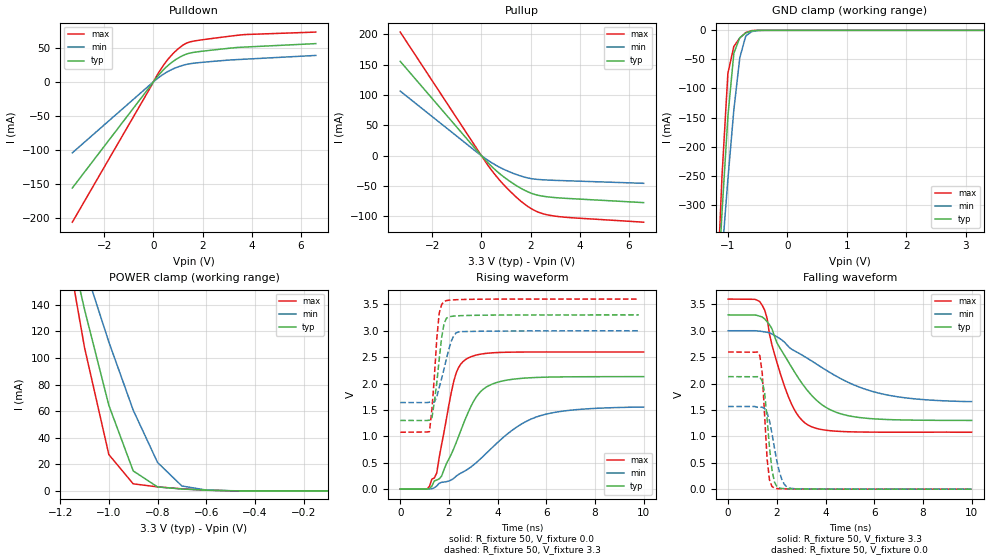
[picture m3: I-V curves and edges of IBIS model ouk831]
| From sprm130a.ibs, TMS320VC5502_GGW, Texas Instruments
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[Model]   ouk831
Model_type   3-state
Enable   Active-Low
Polarity   Non-Inverting
| signals   A, GZ, Y
Vmeas = 1.5
|   typ   min   max
C_comp   1.9825p   1.8925p   2.1938p
|   typ   min   max
[Temperature Range]   25   -40   125
|   typ   min   max
[Voltage Range]   3.30V   3.00V   3.60V
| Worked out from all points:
|   slope of the pulldown table from 0 to 0.495 V, typ, clamps not added: 24 ohm
|   slope of the pullup table from 0 to 0.495 V, typ, clamps not added: 23.8 ohm
|   GND clamp passes 1 mA (typ) near -0.60 V on its own axis
|   POWER clamp passes 1 mA (typ) near -0.65 V on its own axis
|   rising waveform, R_fixture 50, V_fixture 0.0: 20-80 % time 1.22ns typ, 2.5ns min, 648ps max; typ from 0 V to 2.13 V
|   falling waveform, R_fixture 50, V_fixture 3.3: 20-80 % time 1.69ns typ, 3.01ns min, 990ps max; typ from 3.3 V to 1.3 V
|   rising waveform, R_fixture 50, V_fixture 3.3: 20-80 % time 297ps typ, 453ps min, 239ps max; typ from 1.3 V to 3.3 V
|   falling waveform, R_fixture 50, V_fixture 0.0: 20-80 % time 263ps typ, 400ps min, 199ps max; typ from 2.13 V to 0 V
[Pulldown]
|   Voltage   I(typ)   I(min)   I(max)
-3.3V     -155.6mA   -104.1mA   -205.6mA
200mV     9.243mA    5.866mA    12.7mA
600mV     24.13mA    15.28mA    33.3mA
800mV     29.87mA    18.87mA    41.37mA
1.1V      36.63mA    23.02mA    51.08mA
1.3V      39.97mA    25.04mA    55.82mA
1.6V      42.83mA    27mA       59.29mA
3.5V      50.44mA    32.65mA    68.4mA
6.6V      55.87mA    38.54mA    72.75mA
[GND_clamp]
|   Voltage   I(typ)   I(min)   I(max)
-3.3V     -4.907A    -3.696A    -6.377A
-1.2V     -502.7mA   -527mA     -494.6mA
-1.1V     -315.4mA   -388.3mA   -252.9mA
-1V       -148.3mA   -256.2mA   -74.02mA
-900mV    -39.47mA   -137mA     -27.69mA
-800mV    -12.62mA   -47.18mA   -13.24mA
-700mV    -4.559mA   -9.795mA   -3.853mA
-600mV    -881.5uA   -2.2mA     -437.5uA
-400mV    -4.511uA   -47.56uA   -461.1nA
3.3V      222pA      1.904uA    88.82pA
[Pullup]
|   Voltage   I(typ)   I(min)   I(max)
-3.3V     155.5mA    106.5mA    203.9mA
-200mV    9.306mA    6.233mA    12.42mA
300mV     -13.07mA   -8.546mA   -17.75mA
600mV     -24.68mA   -16mA      -33.65mA
900mV     -34.78mA   -22.33mA   -47.64mA
1.4V      -48.81mA   -30.78mA   -67.77mA
1.7V      -55.9mA    -34.78mA   -78.19mA
2V        -61.53mA   -37.68mA   -86.71mA
2.3V      -65.31mA   -39.22mA   -93.01mA
2.9V      -68.83mA   -40.61mA   -99.22mA
3.7V      -71.03mA   -41.73mA   -102.5mA
6.6V      -77.46mA   -45.65mA   -109.8mA
[POWER_clamp]
|   Voltage   I(typ)   I(min)   I(max)
-3.3V     2.105A     1.588A     2.734A
-1.2V     217.1mA    228.2mA    212.4mA
-1.1V     136.6mA    168.7mA    107.9mA
-1V       64.4mA     112mA      27.37mA
-900mV    15.08mA    60.81mA    5.337mA
-800mV    3.01mA     21.44mA    3.051mA
-700mV    1.426mA    3.716mA    1.578mA
-600mV    596.1uA    671uA      553.1uA
-100mV    532.9pA    9.903nA    222pA
[Ramp]
|   I(typ)   I(min)   I(max)
dV/dt_r   1.278/1.221n   0.933/2.501n   1.559/0.646n
dV/dt_f   1.199/1.686n   0.806/3.015n   1.513/0.989n
[Rising Waveform]
R_fixture = 50
V_fixture = 0.0
|  pu_on
|  TIME   V(typ)   V(min)   V(max)
0s        3nV        14nV       2nV
1.1ns     -106.9uV   -189uV     2.744mV
1.4ns     154.8mV    26.97mV    211.4mV
1.5ns     173.4mV    58.87mV    306.4mV
1.7ns     249.3mV    129.8mV    846.7mV
2.2ns     769.4mV    204.7mV    2.046V
2.8ns     1.464V     386.2mV    2.486V
3.7ns     1.974V     752.5mV    2.579V
5.6ns     2.115V     1.368V     2.597V
10ns      2.131V     1.554V     2.598V
[Falling Waveform]
R_fixture = 50
V_fixture = 3.3
V_fixture_min = 3.0
V_fixture_max = 3.6
|  pd_on
|  TIME   V(typ)   V(min)   V(max)
0s        3.3V       3V         3.6V
1.4ns     3.26V      2.985V     3.48V
1.9ns     2.901V     2.914V     2.565V
2.4ns     2.469V     2.74V      1.84V
2.8ns     2.165V     2.6V       1.442V
3.3ns     1.844V     2.466V     1.211V
4.1ns     1.527V     2.232V     1.112V
5.1ns     1.377V     1.988V     1.085V
7ns       1.312V     1.747V     1.078V
10ns      1.302V     1.659V     1.078V
[Rising Waveform]
R_fixture = 50
V_fixture = 3.3
V_fixture_min = 3.0
V_fixture_max = 3.6
|  pd_off
|  TIME   V(typ)   V(min)   V(max)
0s        1.301V     1.64V      1.078V
1.2ns     1.306V     1.646V     1.089V
1.3ns     1.343V     1.65V      1.502V
1.5ns     2.012V     1.743V     2.841V
1.6ns     2.453V     1.922V     3.331V
1.7ns     2.869V     2.094V     3.496V
1.8ns     3.138V     2.279V     3.554V
2.1ns     3.272V     2.806V     3.583V
2.4ns     3.284V     2.978V     3.589V
9.8ns     3.3V       3V         3.6V
[Falling Waveform]
R_fixture = 50
V_fixture = 0.0
|  pu_off
|  TIME   V(typ)   V(min)   V(max)
0s        2.131V     1.565V     2.598V
1.3ns     2.125V     1.554V     2.528V
1.4ns     2.046V     1.551V     2.198V
1.5ns     1.815V     1.526V     1.379V
1.6ns     1.333V     1.447V     573.5mV
1.7ns     780mV      1.291V     169.2mV
1.9ns     136.3mV    784.4mV    20.03mV
2.2ns     14.26mV    192.5mV    6.948mV
2.5ns     6.754mV    21.9mV     4.056mV
10ns      1.954uV    67.49uV    634nV
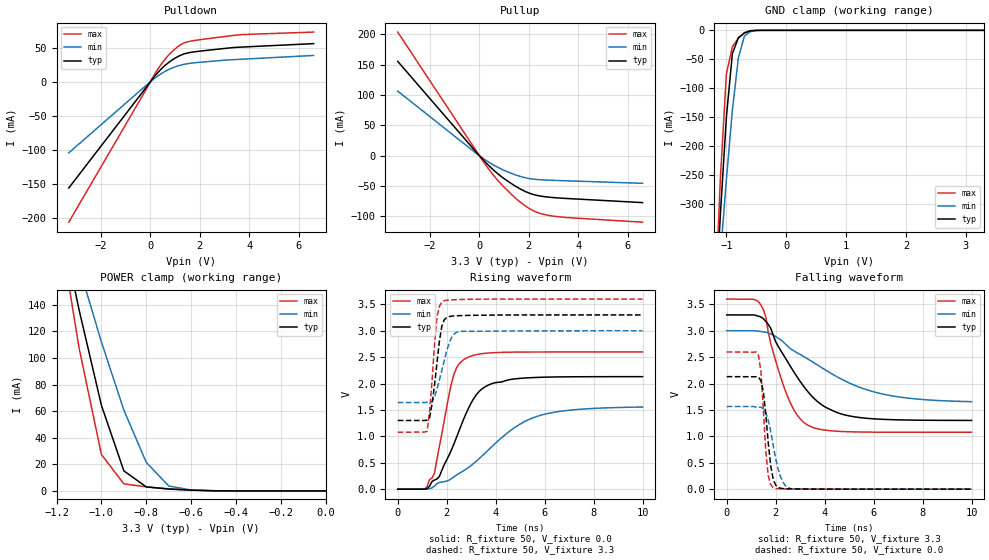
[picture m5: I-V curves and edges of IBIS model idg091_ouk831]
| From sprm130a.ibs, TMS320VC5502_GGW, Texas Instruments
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[Model]   idg091_ouk831
Model_type   I/O
Vinh = 2.00
Vinl = 0.80
Enable   Active-Low
Polarity   Non-Inverting
| signals   A, GZ, Y
Vmeas = 1.5
|   typ   min   max
C_comp   2.425p   2.416p   2.427p
|   typ   min   max
[Temperature Range]   25   -40   125
|   typ   min   max
[Voltage Range]   3.30V   3.00V   3.60V
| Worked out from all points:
|   slope of the pulldown table from 0 to 0.495 V, typ, clamps not added: 24 ohm
|   slope of the pullup table from 0 to 0.495 V, typ, clamps not added: 23.8 ohm
|   GND clamp passes 1 mA (typ) near -0.60 V on its own axis
|   POWER clamp passes 1 mA (typ) near -0.65 V on its own axis
|   rising waveform, R_fixture 50, V_fixture 0.0: 20-80 % time 1.23ns typ, 2.49ns min, 654ps max; typ from 0 V to 2.13 V
|   falling waveform, R_fixture 50, V_fixture 3.3: 20-80 % time 1.69ns typ, 3.02ns min, 1ns max; typ from 3.3 V to 1.3 V
|   rising waveform, R_fixture 50, V_fixture 3.3: 20-80 % time 309ps typ, 462ps min, 249ps max; typ from 1.3 V to 3.3 V
|   falling waveform, R_fixture 50, V_fixture 0.0: 20-80 % time 276ps typ, 422ps min, 219ps max; typ from 2.13 V to 0 V
[Pulldown]
|   Voltage   I(typ)   I(min)   I(max)
-3.3V     -155.6mA   -104.1mA   -205.6mA
200mV     9.243mA    5.866mA    12.7mA
600mV     24.13mA    15.28mA    33.3mA
800mV     29.87mA    18.87mA    41.37mA
1.1V      36.63mA    23.02mA    51.08mA
1.3V      39.97mA    25.04mA    55.82mA
1.6V      42.83mA    27mA       59.29mA
3.5V      50.44mA    32.65mA    68.4mA
6.6V      55.87mA    38.54mA    72.75mA
[GND_clamp]
|   Voltage   I(typ)   I(min)   I(max)
-3.3V     -4.92A     -3.705A    -6.392A
-1.2V     -504.4mA   -528.6mA   -496.3mA
-1.1V     -316.6mA   -389.6mA   -254.1mA
-1V       -149.2mA   -257.2mA   -74.8mA
-900mV    -39.96mA   -137.7mA   -28.16mA
-800mV    -12.87mA   -47.62mA   -13.47mA
-700mV    -4.652mA   -10.02mA   -3.929mA
-600mV    -901uA     -2.282mA   -447.5uA
-400mV    -4.618uA   -49.29uA   -472.1nA
3.3V      177.6pA    1.904uA    222pA
[Pullup]
|   Voltage   I(typ)   I(min)   I(max)
-3.3V     155.5mA    106.5mA    203.9mA
-200mV    9.306mA    6.233mA    12.42mA
300mV     -13.07mA   -8.546mA   -17.75mA
600mV     -24.68mA   -16mA      -33.65mA
900mV     -34.78mA   -22.33mA   -47.64mA
1.4V      -48.81mA   -30.78mA   -67.77mA
1.7V      -55.9mA    -34.78mA   -78.19mA
2V        -61.53mA   -37.68mA   -86.71mA
2.3V      -65.31mA   -39.22mA   -93.01mA
2.9V      -68.83mA   -40.61mA   -99.22mA
3.7V      -71.03mA   -41.73mA   -102.5mA
6.6V      -77.46mA   -45.65mA   -109.8mA
[POWER_clamp]
|   Voltage   I(typ)   I(min)   I(max)
-3.3V     2.105A     1.588A     2.734A
-1.2V     217.1mA    228.2mA    212.4mA
-1.1V     136.6mA    168.7mA    107.9mA
-1V       64.4mA     112mA      27.37mA
-900mV    15.08mA    60.81mA    5.337mA
-800mV    3.01mA     21.44mA    3.051mA
-700mV    1.426mA    3.716mA    1.578mA
-600mV    596.1uA    671uA      553.1uA
0V        1pA        1pA        1pA
[Ramp]
|   I(typ)   I(min)   I(max)
dV/dt_r   1.278/1.223n   0.933/2.494n   1.559/0.650n
dV/dt_f   1.199/1.695n   0.806/3.019n   1.513/0.998n
[Rising Waveform]
R_fixture = 50
V_fixture = 0.0
|  pu_on
|  TIME   V(typ)   V(min)   V(max)
0s        3nV        15nV       3nV
1.1ns     -42.55uV   -125uV     2.351mV
1.5ns     172.1mV    56.5mV     296.1mV
2.2ns     750.8mV    200.4mV    2.015V
2.4ns     979.3mV    267.4mV    2.296V
2.8ns     1.442V     381mV      2.482V
3.2ns     1.781V     524.5mV    2.547V
3.7ns     1.97V      741.5mV    2.578V
5.6ns     2.115V     1.365V     2.597V
10ns      2.131V     1.554V     2.598V
[Falling Waveform]
R_fixture = 50
V_fixture = 3.3
V_fixture_min = 3.0
V_fixture_max = 3.6
|  pd_on
|  TIME   V(typ)   V(min)   V(max)
0s        3.3V       3V         3.6V
1.4ns     3.261V     2.986V     3.486V
1.8ns     3.046V     2.94V      2.762V
2.4ns     2.481V     2.747V     1.861V
2.8ns     2.179V     2.603V     1.46V
3.3ns     1.855V     2.47V      1.215V
4ns       1.562V     2.266V     1.119V
5.1ns     1.379V     1.992V     1.086V
7ns       1.313V     1.749V     1.078V
10ns      1.302V     1.657V     1.078V
[Rising Waveform]
R_fixture = 50
V_fixture = 3.3
V_fixture_min = 3.0
V_fixture_max = 3.6
|  pd_off
|  TIME   V(typ)   V(min)   V(max)
0s        1.301V     1.64V      1.078V
1.2ns     1.307V     1.645V     1.093V
1.3ns     1.352V     1.649V     1.457V
1.4ns     1.607V     1.655V     2.035V
1.6ns     2.378V     1.894V     3.25V
1.8ns     3.083V     2.244V     3.542V
1.9ns     3.207V     2.434V     3.57V
2.2ns     3.276V     2.871V     3.585V
2.5ns     3.286V     2.982V     3.591V
10ns      3.3V       3V         3.6V
[Falling Waveform]
R_fixture = 50
V_fixture = 0.0
|  pu_off
|  TIME   V(typ)   V(min)   V(max)
0s        2.131V     1.565V     2.598V
1.3ns     2.123V     1.554V     2.53V
1.4ns     2.05V      1.55V      2.221V
1.5ns     1.84V      1.524V     1.488V
1.6ns     1.398V     1.451V     692.2mV
1.7ns     864.6mV    1.306V     247mV
1.9ns     189.8mV    831.4mV    26.7mV
2.2ns     17.49mV    235mV      6.826mV
2.6ns     5.644mV    11.73mV    3.52mV
10ns      2.536uV    60.88uV    9.272uV
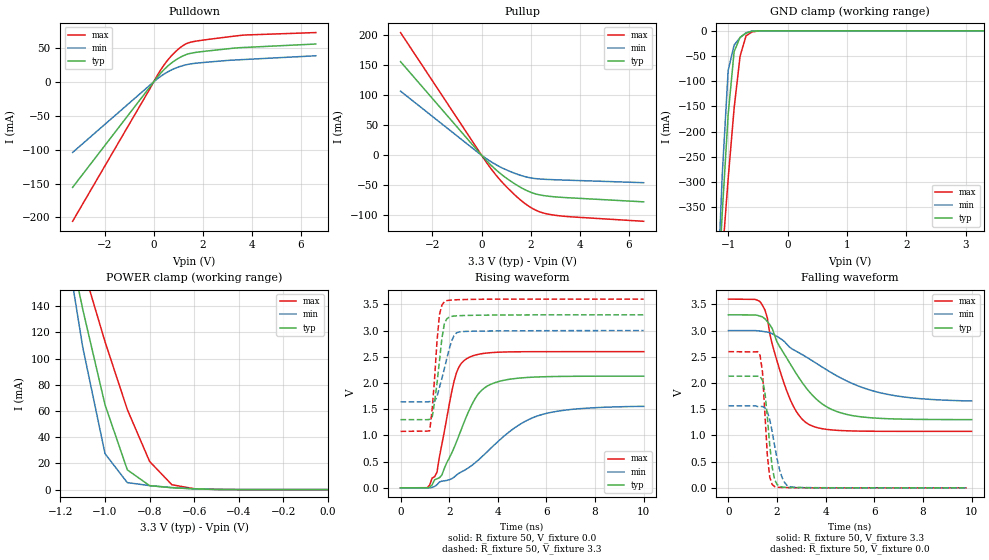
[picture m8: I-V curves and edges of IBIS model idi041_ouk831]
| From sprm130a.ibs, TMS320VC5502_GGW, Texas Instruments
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[Model]   idi041_ouk831
Model_type   I/O
Vinh = 2.00
Vinl = 0.80
Enable   Active-Low
Polarity   Non-Inverting
| signals   A, GZ, Y
Vmeas = 1.5
|   typ   min   max
C_comp   1.7165p   1.6246p   1.9241p
|   typ   min   max
[Temperature Range]   25   -40   125
|   typ   min   max
[Voltage Range]   3.30V   3.00V   3.60V
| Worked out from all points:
|   slope of the pulldown table from 0 to 0.495 V, typ, clamps not added: 24 ohm
|   slope of the pullup table from 0 to 0.495 V, typ, clamps not added: 23.8 ohm
|   GND clamp passes 1 mA (typ) near -0.60 V on its own axis
|   POWER clamp passes 1 mA (typ) near -0.65 V on its own axis
|   rising waveform, R_fixture 50, V_fixture 0.0: 20-80 % time 1.22ns typ, 2.5ns min, 653ps max; typ from 0 V to 2.13 V
|   falling waveform, R_fixture 50, V_fixture 3.3: 20-80 % time 1.69ns typ, 3.01ns min, 996ps max; typ from 3.3 V to 1.3 V
|   rising waveform, R_fixture 50, V_fixture 3.3: 20-80 % time 302ps typ, 454ps min, 244ps max; typ from 1.3 V to 3.3 V
|   falling waveform, R_fixture 50, V_fixture 0.0: 20-80 % time 267ps typ, 406ps min, 207ps max; typ from 2.13 V to 0 V
[Pulldown]
|   Voltage   I(typ)   I(min)   I(max)
-3.3V     -155.6mA   -104.1mA   -205.7mA
200mV     9.245mA    5.867mA    12.7mA
600mV     24.13mA    15.28mA    33.3mA
800mV     29.87mA    18.87mA    41.37mA
1.1V      36.63mA    23.02mA    51.08mA
1.3V      39.97mA    25.04mA    55.82mA
1.6V      42.83mA    27mA       59.29mA
3.5V      50.44mA    32.65mA    68.4mA
6.6V      55.85mA    38.51mA    72.74mA
[GND_clamp]
|   Voltage   I(typ)   I(min)   I(max)
-3.3V     -5.787A    -7.522A    -4.358A
-1.2V     -582.8mA   -571.6mA   -612.7mA
-1.1V     -361.8mA   -286.6mA   -448.9mA
-1V       -165.7mA   -78.53mA   -293.3mA
-900mV    -41.31mA   -28.3mA    -153.6mA
-800mV    -12.91mA   -13.52mA   -50.55mA
-700mV    -4.659mA   -3.937mA   -10.09mA
-600mV    -901.5uA   -447.7uA   -2.271mA
-400mV    -4.618uA   -472nA     -49.07uA
3.3V      133.2pA    0A         1.904uA
[Pullup]
|   Voltage   I(typ)   I(min)   I(max)
-3.3V     155.5mA    106.5mA    203.8mA
-200mV    9.305mA    6.232mA    12.42mA
300mV     -13.07mA   -8.545mA   -17.75mA
600mV     -24.68mA   -16mA      -33.64mA
900mV     -34.78mA   -22.33mA   -47.63mA
1.4V      -48.81mA   -30.78mA   -67.76mA
1.7V      -55.89mA   -34.78mA   -78.18mA
2V        -61.53mA   -37.68mA   -86.7mA
2.3V      -65.31mA   -39.22mA   -93.01mA
2.9V      -68.84mA   -40.61mA   -99.22mA
3.7V      -71.03mA   -41.73mA   -102.5mA
6.6V      -77.47mA   -45.64mA   -109.8mA
[POWER_clamp]
|   Voltage   I(typ)   I(min)   I(max)
-3.3V     2.13A      2.766A     1.607A
-1.2V     219.2mA    214.4mA    230.5mA
-1.1V     137.7mA    108.7mA    170.3mA
-1V       64.77mA    27.43mA    112.9mA
-900mV    15.1mA     5.337mA    61.17mA
-800mV    3.01mA     3.051mA    21.5mA
-700mV    1.426mA    1.578mA    3.717mA
-600mV    596.1uA    553.1uA    671uA
0V        399.7pA    88.82pA    9.948nA
[Ramp]
|   I(typ)   I(min)   I(max)
dV/dt_r   1.278/1.225n   0.933/2.496n   1.559/0.650n
dV/dt_f   1.199/1.692n   0.806/3.021n   1.513/0.996n
[Rising Waveform]
R_fixture = 50
V_fixture = 0.0
|  pu_on
|  TIME   V(typ)   V(min)   V(max)
0s        3nV        16nV       2nV
1.1ns     -136.2uV   -227.7uV   2.664mV
1.5ns     172.5mV    58.47mV    298.6mV
1.7ns     244.2mV    128.6mV    829.6mV
2.2ns     762.6mV    202.4mV    2.033V
2.4ns     994mV      278.2mV    2.305V
2.8ns     1.457V     384mV      2.484V
3.6ns     1.95V      704.6mV    2.574V
5.6ns     2.115V     1.366V     2.597V
10ns      2.131V     1.554V     2.598V
[Falling Waveform]
R_fixture = 50
V_fixture = 3.3
V_fixture_min = 3.0
V_fixture_max = 3.6
|  pd_on
|  TIME   V(typ)   V(min)   V(max)
0s        3.3V       3V         3.6V
1.4ns     3.261V     2.986V     3.482V
1.8ns     3.04V      2.939V     2.741V
2.4ns     2.474V     2.742V     1.847V
2.8ns     2.171V     2.602V     1.452V
3.3ns     1.848V     2.468V     1.212V
4.1ns     1.53V      2.234V     1.112V
5.1ns     1.378V     1.989V     1.085V
7.1ns     1.312V     1.741V     1.078V
10ns      1.302V     1.659V     1.078V
[Rising Waveform]
R_fixture = 50
V_fixture = 3.3
V_fixture_min = 3.0
V_fixture_max = 3.6
|  pd_off
|  TIME   V(typ)   V(min)   V(max)
0s        1.301V     1.641V     1.078V
1.2ns     1.306V     1.646V     1.089V
1.3ns     1.342V     1.649V     1.488V
1.5ns     1.991V     1.741V     2.795V
1.6ns     2.42V      1.914V     3.303V
1.7ns     2.844V     2.083V     3.482V
1.8ns     3.124V     2.267V     3.55V
2.1ns     3.27V      2.799V     3.583V
2.4ns     3.284V     2.974V     3.589V
10ns      3.3V       3V         3.6V
[Falling Waveform]
R_fixture = 50
V_fixture = 0.0
|  pu_off
|  TIME   V(typ)   V(min)   V(max)
0s        2.131V     1.565V     2.598V
1.3ns     2.125V     1.554V     2.531V
1.4ns     2.049V     1.551V     2.211V
1.5ns     1.825V     1.527V     1.412V
1.6ns     1.355V     1.45V      617.1mV
1.7ns     806.4mV    1.298V     200.8mV
1.9ns     159.2mV    803.3mV    23.63mV
2.2ns     16.04mV    204.3mV    7.236mV
2.5ns     7.055mV    25.79mV    4.002mV
9.8ns     3.44uV     67.92uV    1.382uV
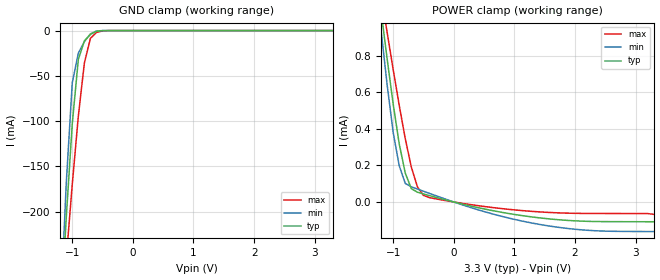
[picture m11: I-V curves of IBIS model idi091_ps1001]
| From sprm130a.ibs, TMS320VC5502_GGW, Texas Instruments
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[Model]   idi091_ps1001
| Input with pullup
Model_type   Input
Polarity   Non-Inverting
| signals   A, Y
Vinl = 0.8V
Vinh = 2.0V
|   typ   min   max
C_comp   1.4592p   1.4336p   1.5063p
|   typ   min   max
[Temperature Range]   25   -40   125
|   typ   min   max
[Voltage Range]   3.30V   3.00V   3.60V
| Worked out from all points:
|   GND clamp passes 1 mA (typ) near -0.61 V on its own axis
|   POWER clamp passes 1 mA (typ) near -1.18 V on its own axis
[GND_clamp]
|   Voltage   I(typ)   I(min)   I(max)
-3.3V     -3.046A    -3.955A    -2.3A
-1.2V     -324.1mA   -319.7mA   -338.8mA
-1.1V     -207.5mA   -169.7mA   -252.5mA
-1V       -102.7mA   -57.61mA   -169.8mA
-900mV    -31.8mA    -24.95mA   -94.42mA
-800mV    -11.42mA   -12.07mA   -35.62mA
-700mV    -4.192mA   -3.56mA    -8.508mA
-600mV    -819.1uA   -409.8uA   -2.049mA
-500mV    -75.22uA   -19.35uA   -368.2uA
-400mV    -4.217uA   -434.7nA   -45.05uA
3.3V      222pA      133.2pA    35.04nA
[POWER_clamp]
|   Voltage   I(typ)   I(min)   I(max)
-3.3V     6.905mA    7.841mA    5.744mA
-1.2V     1.047mA    943.6uA    1.139mA
-1.1V     786.2uA    644.3uA    930.8uA
-1V       537.8uA    382uA      726.9uA
-900mV    318.6uA    198.8uA    530.3uA
-800mV    158.1uA    101.7uA    346.8uA
-700mV    72.97uA    83uA       190.9uA
-600mV    53.62uA    70.93uA    83.38uA
-500mV    44.09uA    58.94uA    36.26uA
500mV     -38.02uA   -52.48uA   -24.54uA
1.4V      -86.44uA   -122uA     -53.97uA
3.3V      -108.3uA   -162.1uA   -67.64uA
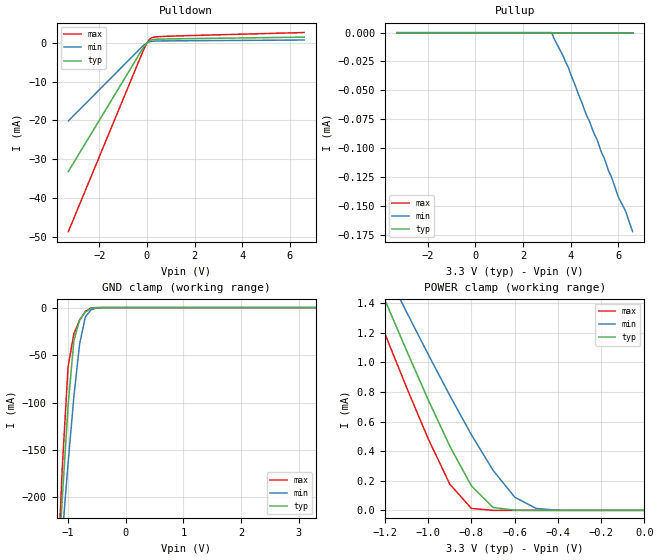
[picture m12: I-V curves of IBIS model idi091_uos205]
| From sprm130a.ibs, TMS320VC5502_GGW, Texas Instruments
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[Model]   idi091_uos205
| Open drain output with input buffer
Model_type   I/O_open_drain
Vinh = 2.00
Vinl = 0.80
Enable   Active-Low
Polarity   Non-Inverting
| signals   A, GZ, Y
Vmeas = 1.5
|   typ   min   max
C_comp   3.010p   2.992p   3.013p
|   typ   min   max
[Temperature Range]   25   -40   125
|   typ   min   max
[Voltage Range]   3.30V   3.00V   3.60V
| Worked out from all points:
|   slope of the pulldown table from 0 to 0.495 V, typ, clamps not added: 511 ohm
|   GND clamp passes 1 mA (typ) near -0.60 V on its own axis
|   POWER clamp passes 1 mA (typ) near -1.08 V on its own axis
[Pulldown]
|   Voltage   I(typ)   I(min)   I(max)
-3.3V     -33.16mA   -20.11mA   -48.66mA
-200mV    -1.676mA   -953uA     -2.637mA
0V        0A         0A         -1uA
100mV     530uA      281uA      888uA
300mV     907uA      480uA      1.509mA
700mV     1.004mA    523uA      1.686mA
6.6V      1.5mA      758uA      2.684mA
[GND_clamp]
|   Voltage   I(typ)   I(min)   I(max)
-3.3V     -2.797A    -2.112A    -3.63A
-1.2V     -307.5mA   -319mA     -305.9mA
-1.1V     -200.8mA   -240.1mA   -168.3mA
-1V       -103.9mA   -164.3mA   -62.58mA
-900mV    -35.2mA    -94.59mA   -27.75mA
-800mV    -12.79mA   -38.44mA   -13.42mA
-700mV    -4.685mA   -9.784mA   -3.964mA
-600mV    -917.7uA   -2.332mA   -456.8uA
-500mV    -84.37uA   -416.9uA   -21.55uA
-400mV    -4.73uA    -50.82uA   -483.2nA
3.3V      266.4pA    59.73nA    177.6pA
[Pullup]
|   Voltage   I(typ)   I(min)   I(max)
-3.3V     0A         0A         0A
3.2V      0A         0A         0A
3.9V      0A         -30uA      0A
4.6V      0A         -68uA      0A
4.8V      0A         -77uA      0A
5.1V      0A         -92uA      0A
5.3V      0A         -104uA     0A
5.4V      0A         -108uA     0A
5.7V      0A         -124uA     0A
6V        0A         -142uA     0A
6.3V      0A         -154uA     0A
6.6V      0A         -172uA     0A
[POWER_clamp]
|   Voltage   I(typ)   I(min)   I(max)
-3.3V     8.994mA    8.041mA    9.273mA
-1.3V     1.769mA    1.927mA    1.563mA
-1.2V     1.421mA    1.632mA    1.193mA
-1.1V     1.08mA     1.34mA     830.7uA
-1V       747.8uA    1.054mA    483.7uA
-900mV    434uA      775.9uA    176.9uA
-800mV    164.8uA    510.7uA    13.06uA
-700mV    19.84uA    270.9uA    142.4nA
-600mV    635nA      89.31uA    1.599nA
-500mV    16.3nA     12.43uA    266.4pA
-400mV    710.5pA    896.8nA    266.4pA
0V        0A         0A         0A
[Ramp]
|   I(typ)   I(min)   I(max)
dV/dt_r   0.028/4.234n   0.027/6.763n   0.030/2.474n
dV/dt_f   1.970/4.234n   1.782/6.763n   2.154/2.474n
R_load = 25000ohms
